One B-rep face of a CAD part: STEP entity #905.
In plain terms, the planar face has unit normal (0, 0, 1).
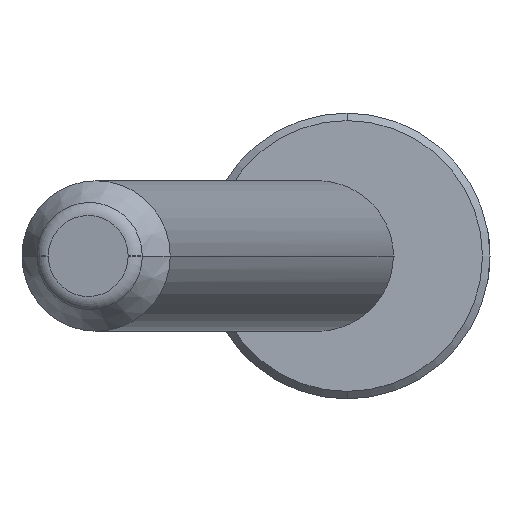
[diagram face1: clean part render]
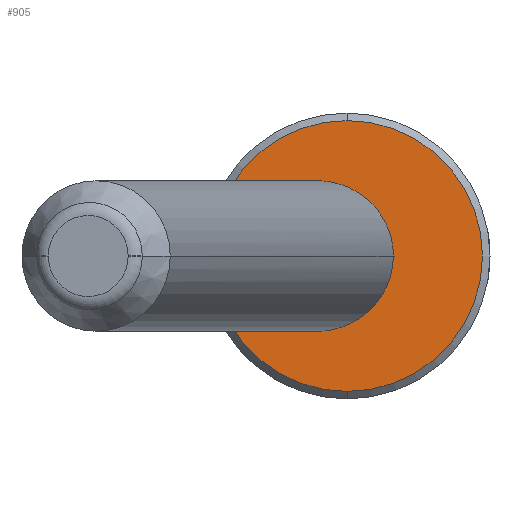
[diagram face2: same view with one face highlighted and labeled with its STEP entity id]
Its self-contained STEP definition (entity closure, numbers rounded to 3 decimals):
#633=CARTESIAN_POINT('Vertex',(0.,18.,36.)) ;
#636=CARTESIAN_POINT('Axis2P3D Location',(0.,0.,36.)) ;
#640=CARTESIAN_POINT('Vertex',(0.,-18.,36.)) ;
#768=CARTESIAN_POINT('Axis2P3D Location',(0.,0.,36.)) ;
#800=CARTESIAN_POINT('Axis2P3D Location',(0.,0.,36.)) ;
#810=CARTESIAN_POINT('Control Point',(-14.154,0.,36.)) ;
#811=CARTESIAN_POINT('Control Point',(-14.154,0.735,36.)) ;
#812=CARTESIAN_POINT('Control Point',(-14.083,1.486,36.)) ;
#813=CARTESIAN_POINT('Control Point',(-13.94,2.243,36.)) ;
#814=CARTESIAN_POINT('Control Point',(-13.51,3.715,36.)) ;
#815=CARTESIAN_POINT('Control Point',(-12.783,5.105,36.)) ;
#816=CARTESIAN_POINT('Control Point',(-12.363,5.75,36.)) ;
#817=CARTESIAN_POINT('Control Point',(-11.485,6.848,36.)) ;
#818=CARTESIAN_POINT('Control Point',(-10.428,7.778,36.)) ;
#819=CARTESIAN_POINT('Control Point',(-9.925,8.157,36.)) ;
#820=CARTESIAN_POINT('Control Point',(-8.999,8.746,36.)) ;
#821=CARTESIAN_POINT('Control Point',(-8.012,9.204,36.)) ;
#822=CARTESIAN_POINT('Control Point',(-7.58,9.375,36.)) ;
#823=CARTESIAN_POINT('Control Point',(-6.837,9.621,36.)) ;
#824=CARTESIAN_POINT('Control Point',(-6.083,9.795,36.)) ;
#825=CARTESIAN_POINT('Control Point',(-5.778,9.853,36.)) ;
#826=CARTESIAN_POINT('Control Point',(-5.316,9.923,36.)) ;
#827=CARTESIAN_POINT('Control Point',(-4.857,9.966,36.)) ;
#828=CARTESIAN_POINT('Control Point',(-4.702,9.978,36.)) ;
#829=CARTESIAN_POINT('Control Point',(-4.391,9.996,36.)) ;
#830=CARTESIAN_POINT('Control Point',(-4.081,10.001,36.)) ;
#831=CARTESIAN_POINT('Control Point',(-3.925,10.001,36.)) ;
#832=CARTESIAN_POINT('Control Point',(-3.615,9.996,36.)) ;
#833=CARTESIAN_POINT('Control Point',(-3.304,9.978,36.)) ;
#834=CARTESIAN_POINT('Control Point',(-3.149,9.967,36.)) ;
#835=CARTESIAN_POINT('Control Point',(-2.393,9.895,36.)) ;
#836=CARTESIAN_POINT('Control Point',(-1.63,9.753,36.)) ;
#837=CARTESIAN_POINT('Control Point',(-1.021,9.59,36.)) ;
#838=CARTESIAN_POINT('Control Point',(0.153,9.177,36.)) ;
#839=CARTESIAN_POINT('Control Point',(1.266,8.583,36.)) ;
#840=CARTESIAN_POINT('Control Point',(1.789,8.251,36.)) ;
#841=CARTESIAN_POINT('Control Point',(2.788,7.501,36.)) ;
#842=CARTESIAN_POINT('Control Point',(3.661,6.607,36.)) ;
#843=CARTESIAN_POINT('Control Point',(4.065,6.122,36.)) ;
#844=CARTESIAN_POINT('Control Point',(4.694,5.237,36.)) ;
#845=CARTESIAN_POINT('Control Point',(5.193,4.285,36.)) ;
#846=CARTESIAN_POINT('Control Point',(5.382,3.866,36.)) ;
#847=CARTESIAN_POINT('Control Point',(5.772,2.849,36.)) ;
#848=CARTESIAN_POINT('Control Point',(6.015,1.806,36.)) ;
#849=CARTESIAN_POINT('Control Point',(6.108,1.198,36.)) ;
#850=CARTESIAN_POINT('Control Point',(6.154,0.593,36.)) ;
#851=CARTESIAN_POINT('Control Point',(6.154,0.,36.)) ;
#852=CARTESIAN_POINT('Vertex',(-14.154,0.,36.)) ;
#854=CARTESIAN_POINT('Vertex',(6.154,0.,36.)) ;
#858=CARTESIAN_POINT('Control Point',(6.154,0.,36.)) ;
#859=CARTESIAN_POINT('Control Point',(6.154,-0.735,36.)) ;
#860=CARTESIAN_POINT('Control Point',(6.083,-1.486,36.)) ;
#861=CARTESIAN_POINT('Control Point',(5.94,-2.243,36.)) ;
#862=CARTESIAN_POINT('Control Point',(5.51,-3.715,36.)) ;
#863=CARTESIAN_POINT('Control Point',(4.783,-5.105,36.)) ;
#864=CARTESIAN_POINT('Control Point',(4.363,-5.75,36.)) ;
#865=CARTESIAN_POINT('Control Point',(3.485,-6.848,36.)) ;
#866=CARTESIAN_POINT('Control Point',(2.428,-7.778,36.)) ;
#867=CARTESIAN_POINT('Control Point',(1.925,-8.157,36.)) ;
#868=CARTESIAN_POINT('Control Point',(0.999,-8.746,36.)) ;
#869=CARTESIAN_POINT('Control Point',(0.012,-9.204,36.)) ;
#870=CARTESIAN_POINT('Control Point',(-0.42,-9.375,36.)) ;
#871=CARTESIAN_POINT('Control Point',(-1.163,-9.621,36.)) ;
#872=CARTESIAN_POINT('Control Point',(-1.917,-9.795,36.)) ;
#873=CARTESIAN_POINT('Control Point',(-2.222,-9.853,36.)) ;
#874=CARTESIAN_POINT('Control Point',(-2.684,-9.923,36.)) ;
#875=CARTESIAN_POINT('Control Point',(-3.143,-9.966,36.)) ;
#876=CARTESIAN_POINT('Control Point',(-3.298,-9.978,36.)) ;
#877=CARTESIAN_POINT('Control Point',(-3.609,-9.996,36.)) ;
#878=CARTESIAN_POINT('Control Point',(-3.919,-10.001,36.)) ;
#879=CARTESIAN_POINT('Control Point',(-4.075,-10.001,36.)) ;
#880=CARTESIAN_POINT('Control Point',(-4.385,-9.996,36.)) ;
#881=CARTESIAN_POINT('Control Point',(-4.696,-9.978,36.)) ;
#882=CARTESIAN_POINT('Control Point',(-4.851,-9.967,36.)) ;
#883=CARTESIAN_POINT('Control Point',(-5.607,-9.895,36.)) ;
#884=CARTESIAN_POINT('Control Point',(-6.37,-9.753,36.)) ;
#885=CARTESIAN_POINT('Control Point',(-6.979,-9.59,36.)) ;
#886=CARTESIAN_POINT('Control Point',(-8.153,-9.177,36.)) ;
#887=CARTESIAN_POINT('Control Point',(-9.266,-8.583,36.)) ;
#888=CARTESIAN_POINT('Control Point',(-9.789,-8.251,36.)) ;
#889=CARTESIAN_POINT('Control Point',(-10.788,-7.501,36.)) ;
#890=CARTESIAN_POINT('Control Point',(-11.661,-6.607,36.)) ;
#891=CARTESIAN_POINT('Control Point',(-12.065,-6.122,36.)) ;
#892=CARTESIAN_POINT('Control Point',(-12.694,-5.237,36.)) ;
#893=CARTESIAN_POINT('Control Point',(-13.193,-4.285,36.)) ;
#894=CARTESIAN_POINT('Control Point',(-13.382,-3.866,36.)) ;
#895=CARTESIAN_POINT('Control Point',(-13.772,-2.849,36.)) ;
#896=CARTESIAN_POINT('Control Point',(-14.015,-1.806,36.)) ;
#897=CARTESIAN_POINT('Control Point',(-14.108,-1.198,36.)) ;
#898=CARTESIAN_POINT('Control Point',(-14.154,-0.593,36.)) ;
#899=CARTESIAN_POINT('Control Point',(-14.154,0.,36.)) ;
#637=DIRECTION('Axis2P3D Direction',(0.,0.,-1.)) ;
#769=DIRECTION('Axis2P3D Direction',(0.,0.,-1.)) ;
#801=DIRECTION('Axis2P3D Direction',(0.,-0.,1.)) ;
#802=DIRECTION('Axis2P3D XDirection',(0.,1.,0.)) ;
#638=AXIS2_PLACEMENT_3D('Circle Axis2P3D',#636,#637,$) ;
#770=AXIS2_PLACEMENT_3D('Circle Axis2P3D',#768,#769,$) ;
#803=AXIS2_PLACEMENT_3D('Plane Axis2P3D',#800,#801,#802) ;
#806=ORIENTED_EDGE('',*,*,#642,.F.) ;
#807=ORIENTED_EDGE('',*,*,#772,.F.) ;
#902=ORIENTED_EDGE('',*,*,#856,.T.) ;
#903=ORIENTED_EDGE('',*,*,#900,.T.) ;
#904=FACE_BOUND('',#901,.T.) ;
#905=ADVANCED_FACE('MANIFOLD_SOLID_BREP #695',(#808,#904),#804,.T.) ;
#809=B_SPLINE_CURVE_WITH_KNOTS('',5,(#810,#811,#812,#813,#814,#815,#816,#817,#818,#819,#820,#821,#822,#823,#824,#825,#826,#827,#828,#829,#830,#831,#832,#833,#834,#835,#836,#837,#838,#839,#840,#841,#842,#843,#844,#845,#846,#847,#848,#849,#850,#851),.UNSPECIFIED.,.F.,.U.,(6,3,3,3,3,3,3,3,3,3,3,3,3,6),(0.,5.521,10.902,15.191,18.476,20.709,21.849,23.006,24.146,28.559,32.885,37.155,40.383,44.843),.UNSPECIFIED.) ;
#857=B_SPLINE_CURVE_WITH_KNOTS('',5,(#858,#859,#860,#861,#862,#863,#864,#865,#866,#867,#868,#869,#870,#871,#872,#873,#874,#875,#876,#877,#878,#879,#880,#881,#882,#883,#884,#885,#886,#887,#888,#889,#890,#891,#892,#893,#894,#895,#896,#897,#898,#899),.UNSPECIFIED.,.F.,.U.,(6,3,3,3,3,3,3,3,3,3,3,3,3,6),(0.,5.521,10.902,15.191,18.476,20.709,21.849,23.006,24.146,28.559,32.885,37.155,40.383,44.843),.UNSPECIFIED.) ;
#639=CIRCLE('generated circle',#638,18.) ;
#771=CIRCLE('generated circle',#770,18.) ;
#642=EDGE_CURVE('',#634,#641,#639,.T.) ;
#772=EDGE_CURVE('',#641,#634,#771,.T.) ;
#856=EDGE_CURVE('',#853,#855,#809,.T.) ;
#900=EDGE_CURVE('',#855,#853,#857,.T.) ;
#805=EDGE_LOOP('',(#806,#807)) ;
#901=EDGE_LOOP('',(#902,#903)) ;
#808=FACE_OUTER_BOUND('',#805,.T.) ;
#804=PLANE('Plane',#803) ;
#634=VERTEX_POINT('',#633) ;
#641=VERTEX_POINT('',#640) ;
#853=VERTEX_POINT('',#852) ;
#855=VERTEX_POINT('',#854) ;
